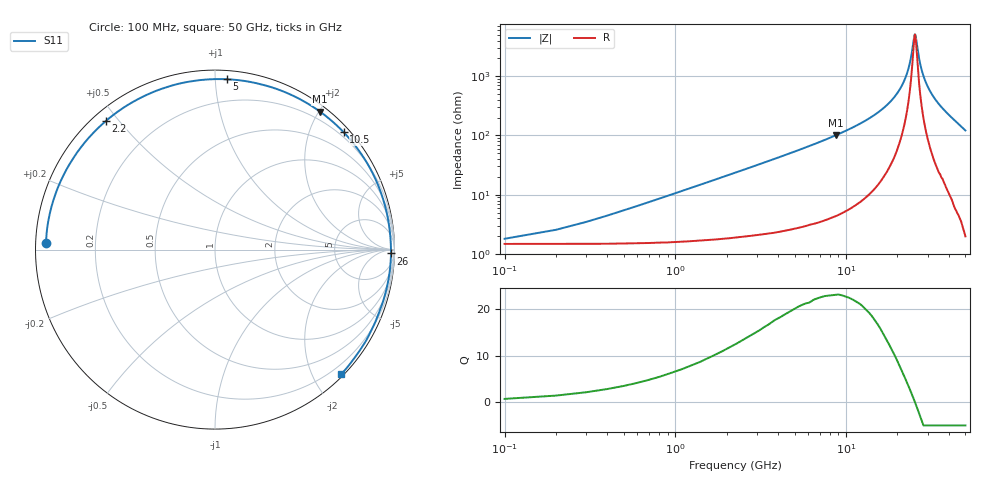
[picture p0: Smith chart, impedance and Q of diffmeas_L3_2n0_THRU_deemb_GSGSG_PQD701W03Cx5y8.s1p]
! Created Wed Mar 15 13:52:24 2023
# hz S ma R 50
! 1 Port Network Data from SP1.SP block
! freq  magS11  angS11
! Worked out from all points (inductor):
!   500 points, 100 MHz to 50 GHz, reference 50 ohm
!   read as one part to ground: L = 1.67 nH near 500 MHz
!   highest Q = 23 at 8.7 GHz (marker M1), where L = 1.84 nH
!   self-resonance near 25.33 GHz
!   S11 on the Smith chart (normalised r, x): 100 MHz: 0.03, +0.02; 2.2 GHz: 0.04, +0.46; 5 GHz: 0.05, +1.07; 10.5 GHz: 0.12, +2.58; 26 GHz: 46, -51; 50 GHz: 0.04, -2.43
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1e8  0.9425 177.6
3e8  0.9426 172.8
5e8  0.9421 168.0
1e9  0.9407 156.2
1.6e9  0.9395 142.9
2.2e9  0.9397 130.4
2.8e9  0.9412 119.0
3.5e9  0.9442 107.1
4.2e9  0.9475 96.5
5e9  0.9514 86.0
5.7e9  0.9547 78.0
6.4e9  0.9578 70.9
7.5e9  0.9622 61.4
8.7e9  0.9661 52.8
9.5e9  0.9682 47.8
1.05e10  0.9703 42.4
1.15e10  0.9721 37.5
1.26e10  0.9738 32.9
1.39e10  0.9754 28.0
1.54e10  0.9767 23.0
1.89e10  0.9785 13.5
2.18e10  0.9792 6.9
2.51e10  0.9804 0.4
2.6e10  0.9807 -1.2
3.13e10  0.9806 -10.6
3.76e10  0.979 -21.1
4.38e10  0.9828 -32.2
5e10  0.9886 -44.7
